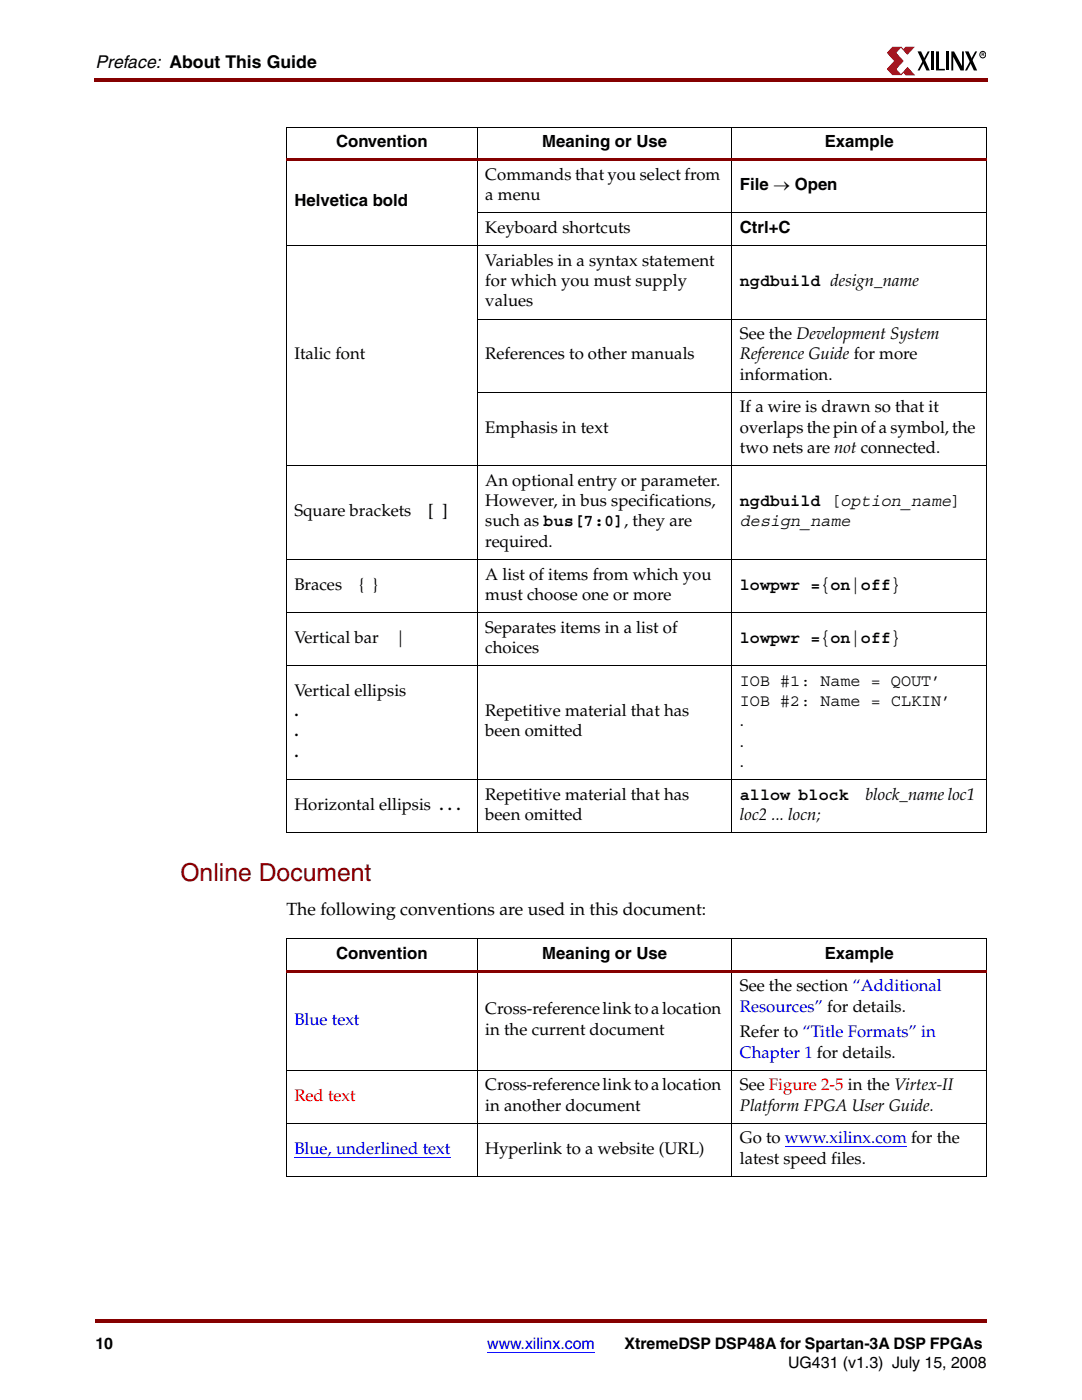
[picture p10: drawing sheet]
<svg xmlns="http://www.w3.org/2000/svg" width="216mm" height="279mm" viewBox="0 0 216 279" stroke-linecap="round" stroke-linejoin="round" font-family="sans-serif">
<defs><g id="words">
<text font-size="4.9" fill="#850000" x="36" y="175.8">Online Document</text>
<g font-size="3.5">
<text x="19" y="13.6">Preface: About This Guide</text>
<text x="57.1" y="182.6">The following conventions are used in this document:</text>
</g>
<g font-size="3.3">
<text x="67.1" y="29.4">Convention</text>
<text x="108.2" y="29.4">Meaning or Use</text>
<text x="164.6" y="29.4">Example</text>
<text x="96.8" y="35.9">Commands that you select from</text>
<text x="58.7" y="41.2">Helvetica bold</text>
<text x="96.8" y="40">a menu</text>
<text x="147.6" y="38">File → Open</text>
<text x="96.8" y="46.5">Keyboard shortcuts</text>
<text x="147.6" y="46.5">Ctrl+C</text>
<text x="96.8" y="53">Variables in a syntax statement</text>
<text x="96.8" y="57.1">for which you must supply</text>
<text x="147.6" y="57.1">ngdbuild design_name</text>
<text x="96.8" y="61.2">values</text>
<text x="58.7" y="71.7">Italic font</text>
<text x="96.8" y="71.7">References to other manuals</text>
<text x="147.6" y="67.7">See the Development System</text>
<text x="147.6" y="71.7">Reference Guide for more</text>
<text x="147.6" y="75.8">information.</text>
<text x="147.6" y="82.3">If a wire is drawn so that it</text>
<text x="96.8" y="86.4">Emphasis in text</text>
<text x="147.6" y="86.4">overlaps the pin of a symbol, the</text>
<text x="147.6" y="90.4">two nets are not connected.</text>
<text x="96.8" y="96.9">An optional entry or parameter.</text>
<text x="96.8" y="101">However, in bus specifications,</text>
<text x="147.6" y="101">ngdbuild [option_name]</text>
<text x="58.7" y="103">Square brackets</text>
<text x="85.4" y="103">[ ]</text>
<text x="96.8" y="105.1">such as bus[7:0], they are</text>
<text x="147.6" y="105.1">design_name</text>
<text x="96.8" y="109.1">required.</text>
<text x="58.7" y="117.7">Braces</text>
<text x="71.6" y="117.7">{ }</text>
<text x="96.8" y="115.7">A list of items from which you</text>
<text x="96.8" y="119.7">must choose one or more</text>
<text x="147.6" y="117.7">lowpwr ={on|off}</text>
<text x="58.7" y="128.3">Vertical bar</text>
<text x="78.9" y="128.3">|</text>
<text x="96.8" y="126.2">Separates items in a list of</text>
<text x="96.8" y="130.3">choices</text>
<text x="147.6" y="128.3">lowpwr ={on|off}</text>
<text x="147.6" y="136.8">IOB #1: Name = QOUT’</text>
<text x="58.7" y="138.9">Vertical ellipsis</text>
<text x="58.7" y="142.9">.</text>
<text x="96.8" y="142.9">Repetitive material that has</text>
<text x="147.6" y="140.9">IOB #2: Name = CLKIN’</text>
<text x="58.7" y="147">.</text>
<text x="96.8" y="147">been omitted</text>
<text x="147.6" y="144.9">.</text>
<text x="147.6" y="149">.</text>
<text x="58.7" y="151">.</text>
<text x="147.6" y="153.1">.</text>
<text x="58.7" y="161.6">Horizontal ellipsis . . .</text>
<text x="96.8" y="159.6">Repetitive material that has</text>
<text x="147.6" y="159.6">allow block</text>
<text x="172.7" y="159.6">block_name loc1</text>
<text x="96.8" y="163.6">been omitted</text>
<text x="147.6" y="163.6">loc2 ... locn;</text>
<text x="67.1" y="191.3">Convention</text>
<text x="108.2" y="191.3">Meaning or Use</text>
<text x="164.6" y="191.3">Example</text>
<text x="147.6" y="197.8">See the section “Additional</text>
<text x="96.8" y="202.4">Cross-reference link to a location</text>
<text x="96.8" y="206.5">in the current document</text>
<text x="147.6" y="207">Refer to “Title Formats” in</text>
<text x="96.8" y="217.6">Cross-reference link to a location</text>
<text x="96.8" y="221.7">in another document</text>
<text x="147.6" y="217.6">See Figure 2-5 in the Virtex-II</text>
<text x="147.6" y="221.7">Platform FPGA User Guide.</text>
<text x="96.8" y="230.2">Hyperlink to a website (URL)</text>
<text x="147.6" y="232.2">latest speed files.</text>
<text x="147.6" y="228.2">Go to www.xilinx.com for the</text>
</g>
<g font-size="3.3" fill="#00f">
<text x="147.6" y="201.9">Resources” for details.</text>
<text x="58.7" y="204.5">Blue text</text>
<text x="147.6" y="211.1">Chapter 1 for details.</text>
<text x="58.7" y="230.2">Blue, underlined text</text>
</g>
<text font-size="3.3" fill="#f00" x="58.7" y="219.6">Red text</text>
<g font-size="3.2">
<text x="19" y="269.2">10</text>
<text x="124.6" y="269.2">XtremeDSP DSP48A for Spartan-3A DSP FPGAs</text>
<text x="157.3" y="273">UG431 (v1.3) July 15, 2008</text>
</g>
<text font-size="3.2" fill="#00f" x="97.2" y="269.2">www.xilinx.com</text>
<text font-size=".9" x="195.8" y="11.2">R</text>
</g></defs>
<path d="M19 263.2h177.8v.7h-177.8z" fill="#850000"/>
<path d="M19 267.1h177.8v9.8h-177.8z" fill="#fff"/>
<path d="M97.2 269.9h21.5" fill="none" stroke="#00f" stroke-width=".2"/>
<g fill="#850000">
<path d="M18.7 15.5h.3v.7h-.3z"/>
<path d="M19 15.5h178.2v.7h-178.2z"/>
</g>
<path d="M177 9.4h19.7v5.6h-19.7z" fill="#fff"/>
<path d="M183.1 10.3h.7l1.7 3.8h-.6zM185.1 10.3h.4l-2 3.8h-.4zM185.7 10.3h.6v3.8h-.6zM186.8 10.3h.6v3.4h1.1v.4h-1.7zM188.8 10.3h.6v3.8h-.6zM189.8 10.3h.6l1.6 2.9v-2.9h.3v3.8h-.6l-1.5-2.8v2.8h-.4z" fill="#000"/>
<path d="M178.1 9.4h1.6l-1 1.1 1.5 1.7-1.5 1.6 1 1.1h-1.6l-1-1.1 1.5-1.6-1.5-1.6z" fill="#8f0127"/>
<path d="M178.1 9.4h1.6l-1 1.1 1.5 1.7-1.5 1.6 1 1.1h-1.6l-1-1.1 1.5-1.6-1.5-1.6z" fill="none" stroke="#8f0127" stroke-width=".2"/>
<g fill="#8f0127" stroke="#8f0127" stroke-width=".2">
<path d="M179.8 9.4l.5 .5 .4-.5h1.6l-1.2 1.4z"/>
<path d="M181.1 13.5l1.3 1.4h-1.6l-.5-.5-.5 .5z"/>
</g>
<path d="M192.6 10.3h.7l1.7 3.8h-.7zM194.6 10.3h.4l-2 3.8h-.4z" fill="#000"/>
<g fill="none" stroke="#000" stroke-width=".2">
<path d="M57.1 25.4h139.8M57.2 25.4v140.7M95.2 25.4v140.8M146 25.4v140.8M196.8 25.4v140.7"/>
<circle cx="196.1" cy="10.9" r=".63"/>
</g>
<path d="M57.1 31.7h139.8v.5h-139.8z" fill="#850000"/>
<g fill="none" stroke="#000" stroke-width=".2">
<path d="M57.1 49h139.8M95.2 42.5h101.7M95.2 63.7h101.7M95.2 78.3h101.7M57.1 93h139.8M57.1 111.7h139.8M57.1 122.2h139.8M57.1 132.8h139.8M57.1 155.6h139.8M57.1 166.2h139.8M57.1 187.3h139.8M57.2 187.4v47.3"/>
<path d="M95.2 187.3v47.5M146 187.3v47.5M196.8 187.4v47.3"/>
</g>
<path d="M58.7 230.9h31.2M156.6 228.9h24.4" fill="none" stroke="#00f" stroke-width=".2"/>
<path d="M57.1 193.6h139.8v.5h-139.8z" fill="#850000"/>
<path d="M57.1 213.6h139.8M57.1 224.2h139.8M57.1 234.8h139.8" fill="none" stroke="#000" stroke-width=".2"/>
<use href="#words"/>
</svg>
